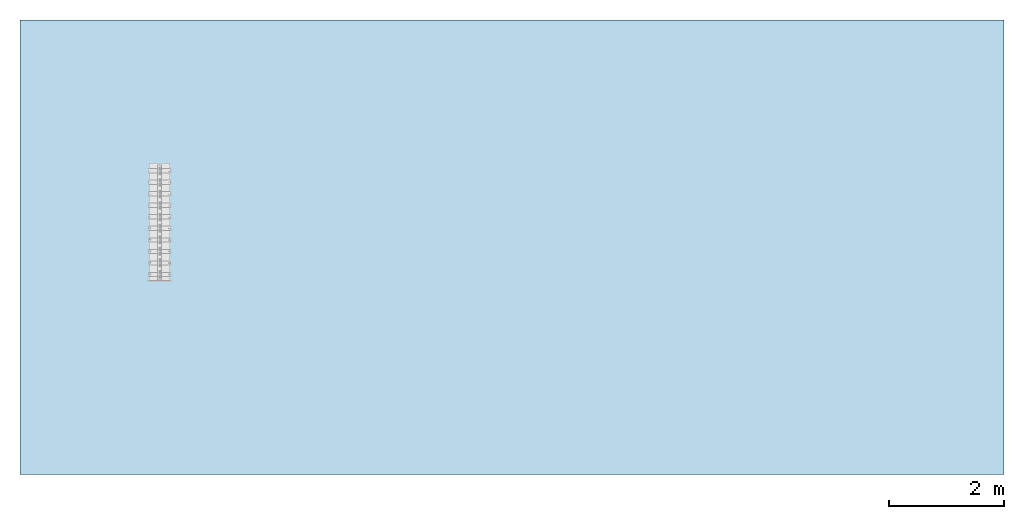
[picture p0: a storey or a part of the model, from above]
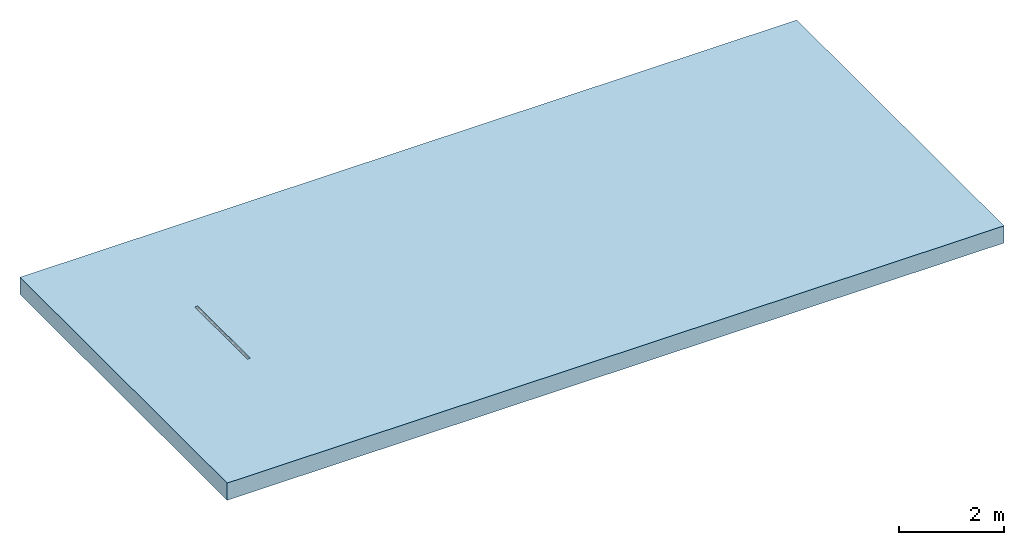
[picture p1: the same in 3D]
Properties of the parts of a building model (IFC2X3)

# File
Description: ViewDefinition [CoordinationView]
File name: 32811 - Q-Guard Edge - D.I.ifc
Time: 2013-07-12T11:19:31
Written by: Autodesk Revit 2013
Made in: 20120221_2030(x64)

# IfcProject, Project Number
LongName: Project Name; Phase: Project Status

# IfcSite, Default
RefLatitude: 42, 21, 30, 344238; RefLongitude: -71, -3, -35, -194702; RefElevation: 0 mm

# IfcBuilding
Pset_BuildingCommon - NumberOfStoreys: 1
Other - Project Issue Date: Issue Date; Project Name: Project Name; Project Status: Project Status; Project Number: Project Number; Client Name: Owner; Project Address: ## Street City, State Zip

# IfcBuildingStorey, Level 1
LongName: Level 1; Elevation: 0 mm
Constraints - Elevation Base: 0; Elevation: 0 mm
Graphics - Symbol at End 1 Default: no; Symbol: M_Level Head - Circle: M_Level Head - Circle; Symbol at End 2 Default: yes; Line Pattern: Center; Line Weight: 1; Color: 0
Dimensions - Computation Height: 0 mm
Identity Data - Building Story: yes; Structural: no; Name: Level 1

# IfcFlowTerminal: 32811 - Q-Guard Edge - D.I, Qmax 350:32811 - Q-Guard Edge - D.I:32811 - Q-Guard Edge - D.I:562865
In: Level 1
Construction - 32880_225-350 Step Connector: no; 42351_350 End Cap (Female end): no; 42351_350 End Cap (Male end): no; E2-QGuard-DuctileIron: yes; V_CoarseE1: yes; E4-QGuard-GalvSteel: no; E3-QFlow-GalvSteel: no; V_Coarse_E5: no; E5-QSlot-GalvSteel: no; E1-QFlow-DuctileIron: no
Constraints - Moves With Nearby Elements: no; Level: Level: Level 1
Identity Data - Mark: 40; e-mail Technical: technical@aco.co.uk; Maintenance Guidelines: http://www.aco.co.uk/download.php?id=220; Product Page URL: http://www.aco.co.uk/product_detail.php?id=79; Model Description: High capacity slot drainage channel system; OmniClass Title: Rainwater Removal; Product Brochure: http://www.aco.co.uk/download.php?id=220; Type Comments: ACO Qmax 350 channel assembly complete with ACO Q-Guard ductile iron edge rail; Product Code: 32811; OmniClass Number: 23.70.50.24; Manufacturer: ACO Technologies plc - ACO Water Management Division; Price: POA - contact ACO; Assembly Description: Rain Water Drainage; Telephone: +44 (0)1462 816666; Assembly Code: D2040; Fax: +44 (0)1462 815895; URL: www.aco.co.uk; e-mail Sales: customersupport@aco.co.uk; Installation Guidelines: http://www.aco.co.uk/download.php?id=220; Model: ACO Qmax 350; Address: ACO Business Park, Hitchin Road, Shefford, Bedfordshire, United Kingdom SG17 5TE; Cost: 0
Phasing - Phase Created: New Construction
Model Properties - Multi-Functional End Cap - Product Code: 42351; Multi-Functional End Cap - Seal Recycled Material Content: 0%; 225-350 Step Connector - Recyclable: Fully recyclable; 225-350 Step Connector - Weight: 0.8 kg; Multi-Functional End Cap - Seal Colour: Black; Multi-Functional End Cap - Weight: 2.6 kg; Multi-Functional End Cap - Channel Recyclable: Fully recyclable; Multi-Functional End Cap - Seal Material: Chloroprene; Multi-Functional End Cap - Dimensions: Ø435mm x 260mm (ØxL); 225-350 Step Connector - Dimensions: Ø435mm x 25mm (ØxL); 225-350 Step Connector - Recycled Material Content: 0%; Multi-Functional End Cap - Channel Recycled Material Content: Variable %; Multi-Functional End Cap - Seal Recyclable: Fully recyclable; Multi-Functional End Cap - Model Description: High capacity slot drainage channel system; Multi-Functional End Cap - Channel Material: Medium Density Polyethylene; 225-350 Step Connector - Material: High Density Polyethylene; Multi-Functional End Cap - Channel Colour: Black; 225-350 Step Connector- Colour: Black; 225-350 Step Connector - Model Description: High capacity slot drainage channel system; 225-350 Step Connector - Product Code: 32880
General - TagNumber: 0; SerialNumber: 0
Other - Revision: 1; Created by: www.aco.co.uk
Green Building Properties - Channel Recyclable: Fully recyclable; Edge Rail Recycled Material Content: Between 40% - 90%; Channel Recycled Material Content: Variable %; Seal Recycled Material Content: 0%; Edge Rail Recyclable: Fully recyclable; Seal Recyclable: Fully recyclable
Materials and Finishes - Seal Colour: Black; Channel Colour: Black; Edge Rail Material: Ductile Iron; Edge Rail Colour: Black; Channel Material: Medium Density Polyethylene; Seal Material: Chloroprene; Edge Rail Finish: ATec coating
Data - Invert Depth: 550mm; Drainage Slot Width: 8mm twin slot; ACO Hydraulic Design Software: http://www.acodesign.co.uk; Concrete Surround Volume - Load Class F 900: 0.45 m³/m; Product Weight: 29.3 kg; Drainage Slot Intake Area: 10925mm²/m; Load Class: A 15 - F 900; Hydraulic Performance: http://www.aco.co.uk/download.php?id=220; Installation - Concrete Grade: Refer to brochure; Installation - Reinforcement Details: Refer to brochure; Concrete Surround Volume - Load Class A 15 - E 600: 0.34 m³/m; Channel C.S.A: 96211mm²; Product Standard: BS EN 1433:2002 CE marked; Product Dimensions: 2000mm x 415mm x 600mm (LxWxH)
Dimensions - Depth Overall: 600 mm; Floor Opening Width: 65 mm; Width Overall: 415 mm; BoreCentre: 370 mm; Length: 2000 mm

# IfcOpeningElement: Opening
In: Level 1
Dimensions - Area: 134960000 mm2; Volume: 53725000000 mm3; Perimeter: 50000 mm; Thickness: 400 mm
Structural - Enable Analytical Model: no; Structural: no
Phasing - Phase Created: New Construction
Constraints - Level: Level: Level 1; Room Bounding: yes; Height Offset From Level: 0 mm; Related to Mass: no
Materials and Finishes - Structural Material: Plant
Analytical Properties - Roughness: 1; Absorptance: 0.1
Construction - Function: 0; Default Thickness: 400 mm
Graphics - Coarse Scale Fill Color: 0

# IfcSlab: Floor:Generic Floor - 400mm, Floor:Generic Floor - 400mm:193825
In: Level 1
PredefinedType: FLOOR; Material: Plant 400 mm
Dimensions - Area: 134960000 mm2; Volume: 53725000000 mm3; Perimeter: 50000 mm; Thickness: 400 mm
Structural - Enable Analytical Model: no; Structural: no
Phasing - Phase Created: New Construction
Constraints - Level: Level: Level 1; Room Bounding: yes; Height Offset From Level: 0 mm; Related to Mass: no
Pset_SlabCommon - Reference: Generic Floor - 400mm; IsExternal: no; LoadBearing: yes
Materials and Finishes - Structural Material: Plant
Analytical Properties - Roughness: 1; Absorptance: 0.1
Construction - Function: 0; Default Thickness: 400 mm
Graphics - Coarse Scale Fill Color: 0
